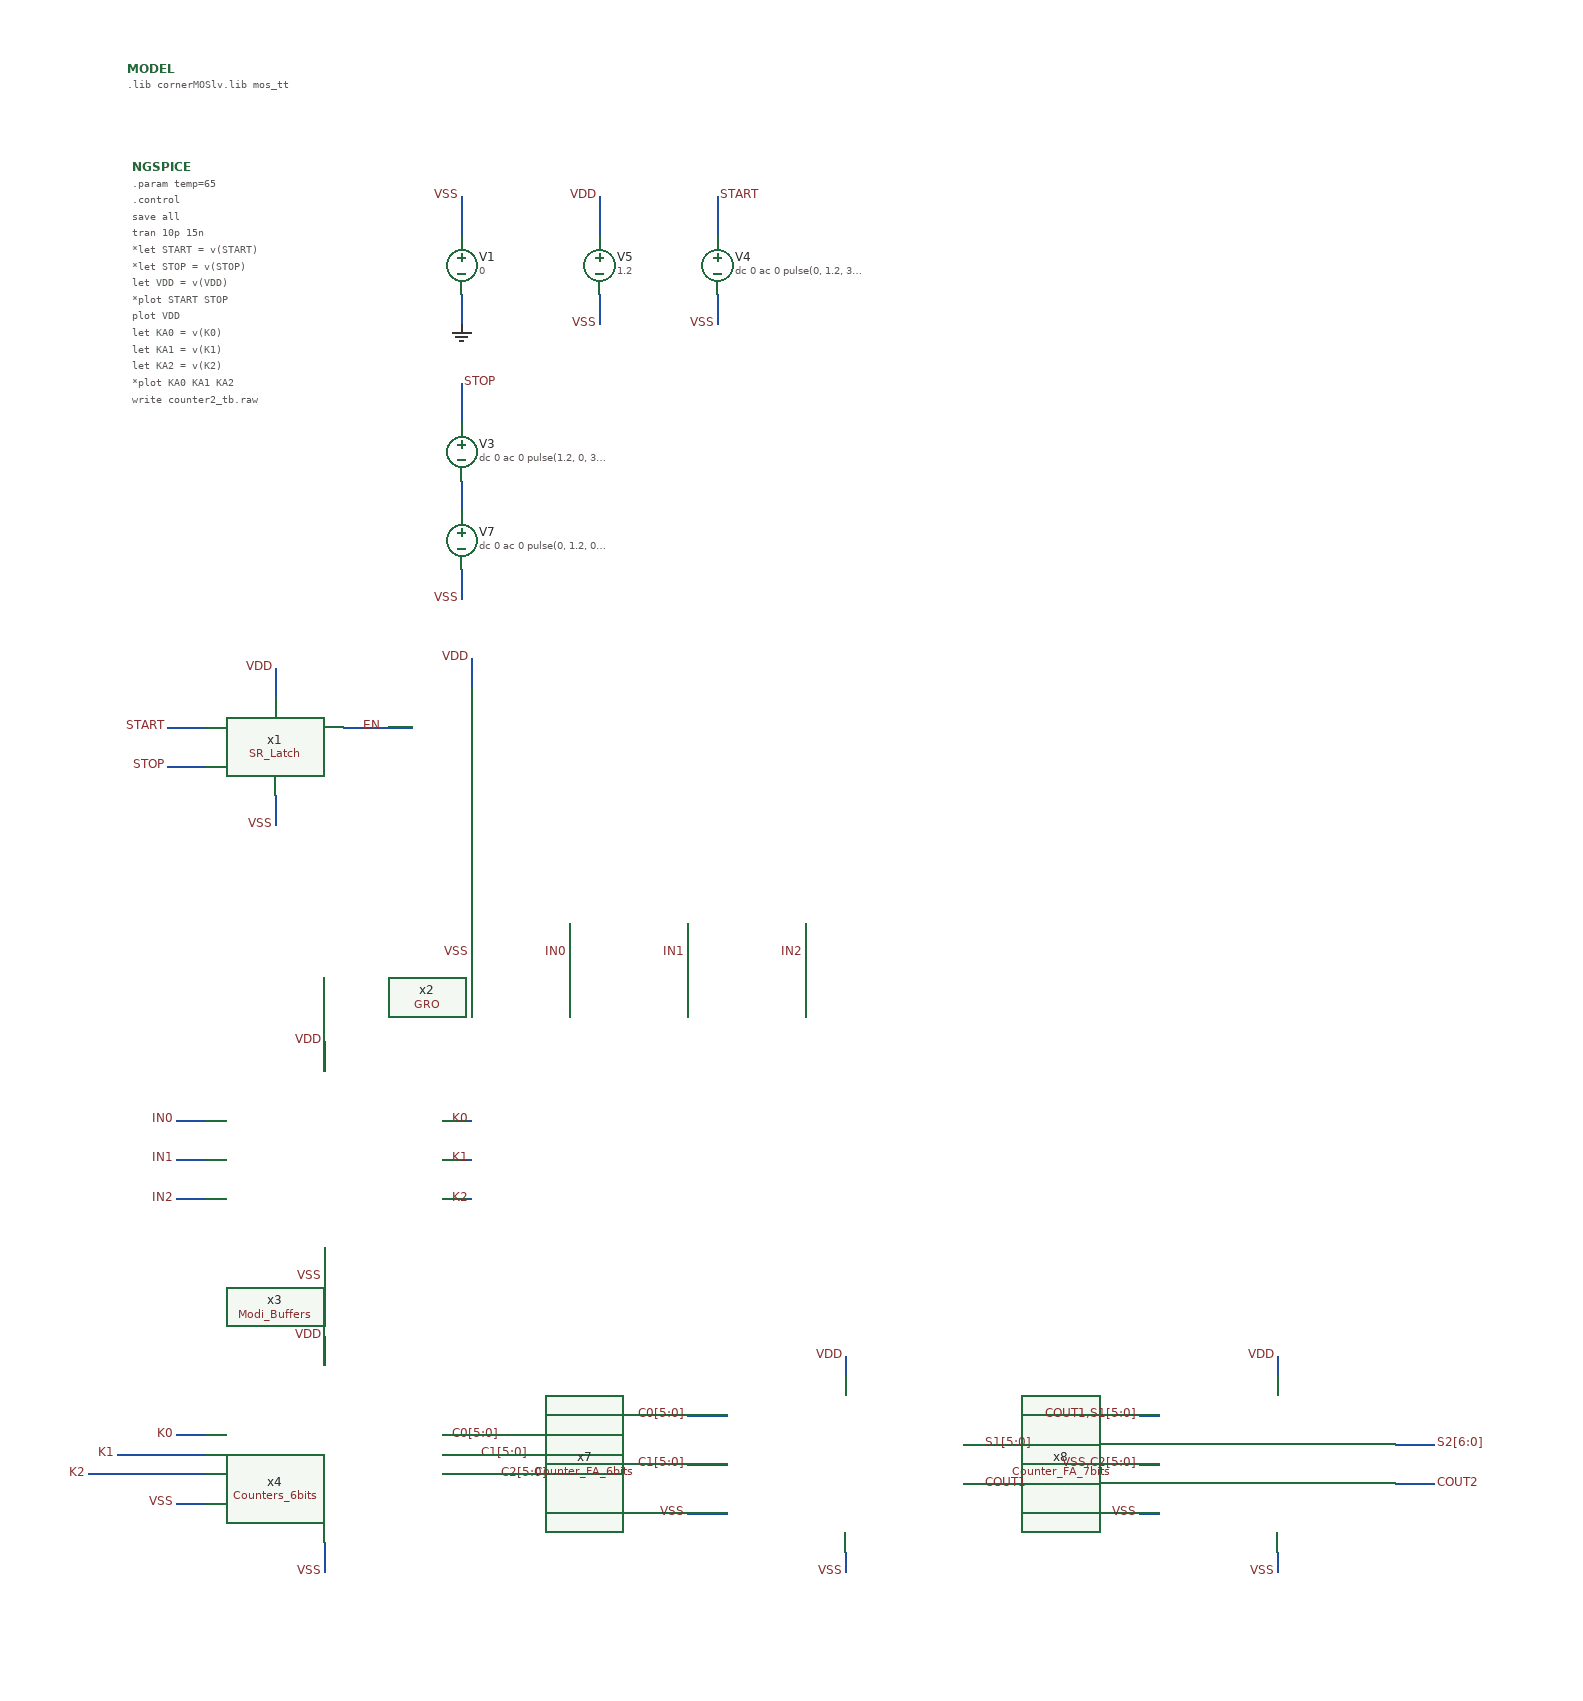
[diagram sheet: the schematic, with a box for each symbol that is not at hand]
v {xschem version=3.4.8RC file_version=1.2}
G {}
K {}
V {}
S {}
F {}
E {}
B 2 1760 -1240 2560 -840 {flags=graph
y2=1.5
ypos1=0
ypos2=2
divy=5
subdivy=1
unity=1
x1=4.7377629e-09
x2=1.2417763e-08
divx=5
subdivx=1


dataset=-1
unitx=1
logx=0
logy=0
hilight_wave=0


y1=-0.2
color="17 8 10"
node="IN0
IN1
IN2"}
B 2 1760 -790 2560 -390 {flags=graph
y2=1.5
ypos1=0
ypos2=2
divy=5
subdivy=1
unity=1
x1=4.7377629e-09
x2=1.2417763e-08
divx=5
subdivx=1


dataset=-1
unitx=1
logx=0
logy=0
hilight_wave=0


y1=-0.2
color="17 8 10"
node="K0
K1
K2"}
B 2 1760 -1680 2560 -1280 {flags=graph
y2=1.5
ypos1=0
ypos2=2
divy=5
subdivy=1
unity=1
x1=4.7377629e-09
x2=1.2417763e-08
divx=5
subdivx=1


dataset=-1
unitx=1
logx=0
logy=0
hilight_wave=0


y1=-0.2
color="17 8 10"
node="START
STOP
RESET"}
B 2 1760 -360 2560 40 {flags=graph
y2=1.5
ypos1=0
ypos2=2
divy=5
subdivy=1
unity=1
x1=4.7377629e-09
x2=1.2417763e-08
divx=5
subdivx=1


dataset=-1
unitx=1
logx=0
logy=0
hilight_wave=0


y1=-0.2
color="17 8 10"
node="C0[0]
C1[0]
C2[0]"}
B 2 2620 -1250 3420 -850 {flags=graph
y1=-0.4
y2=1.5
ypos1=0
ypos2=2
divy=5
subdivy=1
unity=1
x1=4.7377629e-09
x2=1.2417763e-08
divx=5
subdivx=1


dataset=-1
unitx=1
logx=0
logy=0
hilight_wave=0
color=10
node=S2[1]}
B 2 2620 -1670 3420 -1270 {flags=graph
y1=-0.4
y2=1.5
ypos1=0
ypos2=2
divy=5
subdivy=1
unity=1
x1=4.7377629e-09
x2=1.2417763e-08
divx=5
subdivx=1


dataset=-1
unitx=1
logx=0
logy=0
hilight_wave=0
color=8
node=S2[0]}
B 2 3470 -1670 4270 -1270 {flags=graph
y1=-0.4
y2=1.5
ypos1=0
ypos2=2
divy=5
subdivy=1
unity=1
x1=4.7377629e-09
x2=1.2417763e-08
divx=5
subdivx=1


dataset=-1
unitx=1
logx=0
logy=0
hilight_wave=0
color=8
node=S2[4]}
B 2 3470 -1250 4270 -850 {flags=graph
y2=1.5
ypos1=0
ypos2=2
divy=5
subdivy=1
unity=1
x1=4.7377629e-09
x2=1.2417763e-08
divx=5
subdivx=1


dataset=-1
unitx=1
logx=0
logy=0
hilight_wave=0
color=10
node=S2[5]
y1=-0.4}
B 2 2620 -830 3420 -430 {flags=graph
y1=-0.4
y2=1.5
ypos1=0
ypos2=2
divy=5
subdivy=1
unity=1
x1=4.7377629e-09
x2=1.2417763e-08
divx=5
subdivx=1


dataset=-1
unitx=1
logx=0
logy=0
hilight_wave=0
color=7
node=S2[2]}
B 2 3470 -370 4270 30 {flags=graph
y2=1.5
ypos1=0
ypos2=2
divy=5
subdivy=1
unity=1
x1=4.7377629e-09
x2=1.2417763e-08
divx=5
subdivx=1


dataset=-1
unitx=1
logx=0
logy=0
hilight_wave=0


y1=-0.4
color=7
node=COUT2}
B 2 2620 -370 3420 30 {flags=graph
y1=-0.4
y2=1.5
ypos1=0
ypos2=2
divy=5
subdivy=1
unity=1
x1=4.7377629e-09
x2=1.2417763e-08
divx=5
subdivx=1


dataset=-1
unitx=1
logx=0
logy=0
hilight_wave=0


color=11
node=S2[3]}
B 2 3470 -800 4270 -400 {flags=graph
y2=1.5
ypos1=0
ypos2=2
divy=5
subdivy=1
unity=1
x1=4.7377629e-09
x2=1.2417763e-08
divx=5
subdivx=1


dataset=-1
unitx=1
logx=0
logy=0
hilight_wave=0
color=10
node=S2[6]
y1=-0.4}
N 420 -1440 420 -1410 {lab=GND}
N 420 -1540 420 -1500 {lab=VSS}
N 420 -1160 420 -1130 {lab=VSS}
N 680 -1440 680 -1410 {lab=VSS}
N 420 -1350 420 -1310 {lab=STOP}
N 680 -1540 680 -1500 {lab=START}
N 560 -1440 560 -1410 {lab=VSS}
N 560 -1540 560 -1500 {lab=VDD}
N 420 -1250 420 -1220 {lab=VSS}
N 120 -1000 160 -1000 {lab=START}
N 120 -960 160 -960 {lab=STOP}
N 230 -1060 230 -1030 {lab=VDD}
N 230 -930 230 -900 {lab=VSS}
N 430 -1070 430 -1040 {lab=VDD}
N 300 -1000 370 -1000 {lab=EN}
N 280 -470 280 -440 {lab=VSS}
N 530 -800 530 -770 {lab=IN0}
N 650 -800 650 -770 {lab=IN1}
N 770 -800 770 -770 {lab=IN2}
N 400 -600 430 -600 {lab=K0}
N 400 -560 430 -560 {lab=K1}
N 400 -520 430 -520 {lab=K2}
N 130 -600 160 -600 {lab=IN0}
N 130 -560 160 -560 {lab=IN1}
N 130 -520 160 -520 {lab=IN2}
N 430 -800 430 -770 {lab=VSS}
N 280 -680 280 -650 {lab=VDD}
N 280 -170 280 -140 {lab=VSS}
N 280 -380 280 -350 {lab=VDD}
N 130 -280 160 -280 {lab=K0}
N 70 -260 160 -260 {lab=K1}
N 40 -240 160 -240 {lab=K2}
N 130 -210 160 -210 {lab=VSS}
N 400 -280 460 -280 {lab=C0[5:0]}
N 400 -260 490 -260 {lab=C1[5:0]}
N 400 -240 510 -240 {lab=C2[5:0]}
N 810 -360 810 -340 {lab=VDD}
N 1250 -360 1250 -340 {lab=VDD}
N 810 -160 810 -140 {lab=VSS}
N 1250 -160 1250 -140 {lab=VSS}
N 1370 -270 1410 -270 {lab=S2[6:0]}
N 1370 -230 1410 -230 {lab=COUT2}
N 650 -300 690 -300 {lab=C0[5:0]}
N 650 -250 690 -250 {lab=C1[5:0]}
N 650 -200 690 -200 {lab=VSS}
N 930 -270 950 -270 {lab=S1[5:0]}
N 930 -230 950 -230 {lab=COUT1}
N 1110 -200 1130 -200 {lab=VSS}
N 1110 -250 1130 -250 {lab=VSS,C2[5:0]}
N 1110 -300 1130 -300 {lab=COUT1,S1[5:0]}
C {vsource.sym} 420 -1470 0 0 {name=V1 value=0 savecurrent=false
}
C {gnd.sym} 420 -1410 0 0 {name=l1 lab=GND
}
C {lab_wire.sym} 420 -1540 0 0 {name=p1 sig_type=std_logic lab=VSS
}
C {lab_wire.sym} 420 -1130 0 0 {name=p4 sig_type=std_logic lab=VSS
}
C {lab_wire.sym} 680 -1410 0 0 {name=p5 sig_type=std_logic lab=VSS
}
C {lab_wire.sym} 420 -1350 0 1 {name=p7 sig_type=std_logic lab=STOP
}
C {lab_wire.sym} 680 -1540 0 1 {name=p8 sig_type=std_logic lab=START
}
C {vsource.sym} 560 -1470 0 0 {name=V5 value=1.2 savecurrent=false
}
C {lab_wire.sym} 560 -1410 0 0 {name=p12 sig_type=std_logic lab=VSS
}
C {vsource.sym} 680 -1470 0 0 {name=V4 value="dc 0 ac 0 pulse(0, 1.2, 3n, 50p, 50p, 10n, 20n)" savecurrent=false
}
C {devices/code_shown.sym} 85 -1570 0 0 {name=NGSPICE only_toplevel=true 
value="
.param temp=65


.control
save all 
tran 10p 15n
*let START = v(START)
*let STOP = v(STOP)
let VDD = v(VDD)

*plot START STOP
plot VDD

let KA0 = v(K0)
let KA1 = v(K1)
let KA2 = v(K2)

*plot KA0 KA1 KA2

write counter2_tb.raw
*set appendwrite

.endc
"}
C {devices/launcher.sym} 535 -1625 0 0 {name=h5
descr="load waves Ctrl + left click" 
tclcommand="xschem raw_read $netlist_dir/counter2_tb.raw tran"
}
C {devices/launcher.sym} 535 -1685 0 0 {name=h1
descr="simulate" 
tclcommand="xschem save; xschem netlist; xschem simulate"
}
C {devices/code_shown.sym} 80 -1670 0 0 {name=MODEL only_toplevel=true
format="tcleval( @value )"
value="
.lib cornerMOSlv.lib mos_tt
"}
C {lab_wire.sym} 230 -900 0 0 {name=p2 sig_type=std_logic lab=VSS
}
C {vsource.sym} 420 -1190 0 0 {name=V7 value="dc 0 ac 0 pulse(0, 1.2, 0, 500p, 500p, 3n, 0)" savecurrent=false
spice_ignore=short}
C {lab_wire.sym} 430 -1070 0 0 {name=p21 sig_type=std_logic lab=VDD
}
C {lab_wire.sym} 560 -1540 0 0 {name=p13 sig_type=std_logic lab=VDD
}
C {SR_Latch.sym} 140 -890 0 0 {name=x1}
C {lab_wire.sym} 230 -1060 0 0 {name=p19 sig_type=std_logic lab=VDD
}
C {lab_wire.sym} 120 -1000 0 0 {name=p20 sig_type=std_logic lab=START
}
C {lab_wire.sym} 120 -960 0 0 {name=p22 sig_type=std_logic lab=STOP
}
C {lab_wire.sym} 340 -1000 0 0 {name=p33 sig_type=std_logic lab=EN
}
C {GRO.sym} 370 -780 0 0 {name=x2}
C {lab_wire.sym} 280 -440 0 0 {name=p10 sig_type=std_logic lab=VSS
}
C {lab_wire.sym} 530 -770 0 0 {name=p11 sig_type=std_logic lab=IN0
}
C {lab_wire.sym} 650 -770 0 0 {name=p14 sig_type=std_logic lab=IN1
}
C {lab_wire.sym} 770 -770 0 0 {name=p15 sig_type=std_logic lab=IN2
}
C {Modi_Buffers.sym} 60 -380 0 0 {name=x3
}
C {lab_wire.sym} 430 -600 3 1 {name=p3 sig_type=std_logic lab=K0
}
C {lab_wire.sym} 430 -560 3 1 {name=p6 sig_type=std_logic lab=K1
}
C {lab_wire.sym} 430 -520 3 1 {name=p9 sig_type=std_logic lab=K2
}
C {lab_wire.sym} 130 -600 1 0 {name=p16 sig_type=std_logic lab=IN0
}
C {lab_wire.sym} 130 -560 1 0 {name=p17 sig_type=std_logic lab=IN1
}
C {lab_wire.sym} 130 -520 1 0 {name=p18 sig_type=std_logic lab=IN2
}
C {lab_wire.sym} 430 -770 0 0 {name=p23 sig_type=std_logic lab=VSS
}
C {lab_wire.sym} 280 -680 0 0 {name=p24 sig_type=std_logic lab=VDD
}
C {Counters_6bits.sym} 60 -110 0 0 {name=x4
}
C {lab_wire.sym} 280 -140 0 0 {name=p25 sig_type=std_logic lab=VSS
}
C {lab_wire.sym} 280 -380 0 0 {name=p26 sig_type=std_logic lab=VDD
}
C {lab_wire.sym} 130 -280 1 0 {name=p27 sig_type=std_logic lab=K0
}
C {lab_wire.sym} 70 -260 1 0 {name=p28 sig_type=std_logic lab=K1
}
C {lab_wire.sym} 40 -240 1 0 {name=p29 sig_type=std_logic lab=K2
}
C {lab_wire.sym} 130 -210 3 0 {name=p30 sig_type=std_logic lab=VSS
}
C {lab_wire.sym} 460 -280 3 1 {name=p35 sig_type=std_logic lab=C0[5:0]
}
C {lab_wire.sym} 490 -260 3 1 {name=p38 sig_type=std_logic lab=C1[5:0]
}
C {lab_wire.sym} 510 -240 3 1 {name=p39 sig_type=std_logic lab=C2[5:0]
}
C {vsource.sym} 420 -1280 0 0 {name=V3 value="dc 0 ac 0 pulse(1.2, 0, 3n, 50p, 50p, 10n, 20n)" savecurrent=false
}
C {Counter_FA_6bits.sym} 670 -160 0 0 {name=x7
}
C {Counter_FA_7bits.sym} 870 -80 0 0 {name=x8
}
C {lab_wire.sym} 1250 -140 0 0 {name=p31 sig_type=std_logic lab=VSS
}
C {lab_wire.sym} 810 -140 0 0 {name=p32 sig_type=std_logic lab=VSS
}
C {lab_wire.sym} 1250 -360 0 0 {name=p34 sig_type=std_logic lab=VDD
}
C {lab_wire.sym} 810 -360 0 0 {name=p36 sig_type=std_logic lab=VDD
}
C {lab_wire.sym} 1110 -300 0 0 {name=p37 sig_type=std_logic lab=COUT1,S1[5:0]
}
C {lab_wire.sym} 650 -300 0 0 {name=p40 sig_type=std_logic lab=C0[5:0]
}
C {lab_wire.sym} 650 -250 0 0 {name=p41 sig_type=std_logic lab=C1[5:0]
}
C {lab_wire.sym} 1110 -250 0 0 {name=p42 sig_type=std_logic lab=VSS,C2[5:0]
}
C {lab_wire.sym} 650 -200 0 0 {name=p43 sig_type=std_logic lab=VSS
}
C {lab_wire.sym} 1110 -200 0 0 {name=p44 sig_type=std_logic lab=VSS
}
C {lab_wire.sym} 950 -270 0 1 {name=p45 sig_type=std_logic lab=S1[5:0]
}
C {lab_wire.sym} 950 -230 0 1 {name=p46 sig_type=std_logic lab=COUT1
}
C {lab_wire.sym} 1410 -230 0 1 {name=p47 sig_type=std_logic lab=COUT2
}
C {lab_wire.sym} 1410 -270 0 1 {name=p49 sig_type=std_logic lab=S2[6:0]
}
